VERSION 5.7 ;
  DIVIDERCHAR "/" ;
  BUSBITCHARS "[]" ;
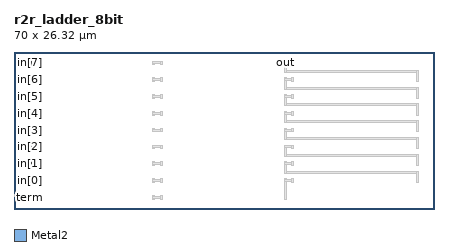
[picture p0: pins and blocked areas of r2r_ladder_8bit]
MACRO r2r_ladder_8bit
  CLASS BLOCK ;
  FOREIGN r2r_ladder_8bit 0.000 0.000 ;
  ORIGIN 0.000 0.000 ;
  SIZE 70.000 BY 26.320 ;
  SYMMETRY X Y ;
  PIN term
    DIRECTION INPUT ;
    USE SIGNAL ;
    PORT
      LAYER Metal2 ;
        RECT 2.340 1.560 2.900 2.360 ;
    END
  END term
  PIN in[0]
    DIRECTION INPUT ;
    USE SIGNAL ;
    PORT
      LAYER Metal2 ;
        RECT 2.340 4.360 2.900 5.160 ;
    END
  END in[0]
  PIN in[1]
    DIRECTION INPUT ;
    USE SIGNAL ;
    PORT
      LAYER Metal2 ;
        RECT 2.340 7.160 2.900 7.960 ;
    END
  END in[1]
  PIN in[2]
    DIRECTION INPUT ;
    USE SIGNAL ;
    PORT
      LAYER Metal2 ;
        RECT 2.340 9.960 2.900 10.760 ;
    END
  END in[2]
  PIN in[3]
    DIRECTION INPUT ;
    USE SIGNAL ;
    PORT
      LAYER Metal2 ;
        RECT 2.340 12.760 2.900 13.560 ;
    END
  END in[3]
  PIN in[4]
    DIRECTION INPUT ;
    USE SIGNAL ;
    PORT
      LAYER Metal2 ;
        RECT 2.340 15.560 2.900 16.360 ;
    END
  END in[4]
  PIN in[5]
    DIRECTION INPUT ;
    USE SIGNAL ;
    PORT
      LAYER Metal2 ;
        RECT 2.340 18.360 2.900 19.160 ;
    END
  END in[5]
  PIN in[6]
    DIRECTION INPUT ;
    USE SIGNAL ;
    PORT
      LAYER Metal2 ;
        RECT 2.340 21.160 2.900 21.960 ;
    END
  END in[6]
  PIN in[7]
    DIRECTION INPUT ;
    USE SIGNAL ;
    PORT
      LAYER Metal2 ;
        RECT 2.340 23.960 2.900 24.760 ;
    END
  END in[7]
  PIN out
    DIRECTION OUTPUT ;
    USE SIGNAL ;
    PORT
      LAYER Metal2 ;
        RECT 44.920 23.960 45.480 24.760 ;
    END
  END out
  OBS
      LAYER Metal1 ;
        RECT 2.450 2.160 2.790 2.260 ;
        RECT 2.420 1.760 2.820 2.160 ;
        RECT 2.450 1.660 2.790 1.760 ;
        RECT 23.110 1.660 23.450 1.790 ;
        RECT 23.110 2.130 23.450 2.260 ;
        RECT 23.110 1.790 24.370 2.130 ;
        RECT 24.370 1.660 24.710 2.260 ;
        RECT 2.450 4.960 2.790 5.060 ;
        RECT 2.420 4.560 2.820 4.960 ;
        RECT 2.450 4.460 2.790 4.560 ;
        RECT 23.110 4.460 23.450 4.590 ;
        RECT 23.110 4.930 23.450 5.060 ;
        RECT 23.110 4.590 24.370 4.930 ;
        RECT 24.370 4.460 24.710 5.060 ;
        RECT 45.030 1.660 45.370 4.590 ;
        RECT 45.030 4.930 45.370 5.060 ;
        RECT 45.030 4.590 46.290 4.930 ;
        RECT 46.290 4.460 46.630 5.060 ;
        RECT 2.450 7.760 2.790 7.860 ;
        RECT 2.420 7.360 2.820 7.760 ;
        RECT 2.450 7.260 2.790 7.360 ;
        RECT 23.110 7.260 23.450 7.390 ;
        RECT 23.110 7.730 23.450 7.860 ;
        RECT 23.110 7.390 24.370 7.730 ;
        RECT 24.370 7.260 24.710 7.860 ;
        RECT 45.370 5.990 67.150 6.330 ;
        RECT 45.030 5.990 45.370 7.390 ;
        RECT 67.150 4.460 67.490 6.330 ;
        RECT 45.030 7.730 45.370 7.860 ;
        RECT 45.030 7.390 46.290 7.730 ;
        RECT 46.290 7.260 46.630 7.860 ;
        RECT 2.450 10.560 2.790 10.660 ;
        RECT 2.420 10.160 2.820 10.560 ;
        RECT 2.450 10.060 2.790 10.160 ;
        RECT 23.110 10.060 23.450 10.190 ;
        RECT 23.110 10.530 23.450 10.660 ;
        RECT 23.110 10.190 24.370 10.530 ;
        RECT 24.370 10.060 24.710 10.660 ;
        RECT 45.370 8.790 67.150 9.130 ;
        RECT 45.030 8.790 45.370 10.190 ;
        RECT 67.150 7.260 67.490 9.130 ;
        RECT 45.030 10.530 45.370 10.660 ;
        RECT 45.030 10.190 46.290 10.530 ;
        RECT 46.290 10.060 46.630 10.660 ;
        RECT 2.450 13.360 2.790 13.460 ;
        RECT 2.420 12.960 2.820 13.360 ;
        RECT 2.450 12.860 2.790 12.960 ;
        RECT 23.110 12.860 23.450 12.990 ;
        RECT 23.110 13.330 23.450 13.460 ;
        RECT 23.110 12.990 24.370 13.330 ;
        RECT 24.370 12.860 24.710 13.460 ;
        RECT 45.370 11.590 67.150 11.930 ;
        RECT 45.030 11.590 45.370 12.990 ;
        RECT 67.150 10.060 67.490 11.930 ;
        RECT 45.030 13.330 45.370 13.460 ;
        RECT 45.030 12.990 46.290 13.330 ;
        RECT 46.290 12.860 46.630 13.460 ;
        RECT 2.450 16.160 2.790 16.260 ;
        RECT 2.420 15.760 2.820 16.160 ;
        RECT 2.450 15.660 2.790 15.760 ;
        RECT 23.110 15.660 23.450 15.790 ;
        RECT 23.110 16.130 23.450 16.260 ;
        RECT 23.110 15.790 24.370 16.130 ;
        RECT 24.370 15.660 24.710 16.260 ;
        RECT 45.370 14.390 67.150 14.730 ;
        RECT 45.030 14.390 45.370 15.790 ;
        RECT 67.150 12.860 67.490 14.730 ;
        RECT 45.030 16.130 45.370 16.260 ;
        RECT 45.030 15.790 46.290 16.130 ;
        RECT 46.290 15.660 46.630 16.260 ;
        RECT 2.450 18.960 2.790 19.060 ;
        RECT 2.420 18.560 2.820 18.960 ;
        RECT 2.450 18.460 2.790 18.560 ;
        RECT 23.110 18.460 23.450 18.590 ;
        RECT 23.110 18.930 23.450 19.060 ;
        RECT 23.110 18.590 24.370 18.930 ;
        RECT 24.370 18.460 24.710 19.060 ;
        RECT 45.370 17.190 67.150 17.530 ;
        RECT 45.030 17.190 45.370 18.590 ;
        RECT 67.150 15.660 67.490 17.530 ;
        RECT 45.030 18.930 45.370 19.060 ;
        RECT 45.030 18.590 46.290 18.930 ;
        RECT 46.290 18.460 46.630 19.060 ;
        RECT 2.450 21.760 2.790 21.860 ;
        RECT 2.420 21.360 2.820 21.760 ;
        RECT 2.450 21.260 2.790 21.360 ;
        RECT 23.110 21.260 23.450 21.390 ;
        RECT 23.110 21.730 23.450 21.860 ;
        RECT 23.110 21.390 24.370 21.730 ;
        RECT 24.370 21.260 24.710 21.860 ;
        RECT 45.370 19.990 67.150 20.330 ;
        RECT 45.030 19.990 45.370 21.390 ;
        RECT 67.150 18.460 67.490 20.330 ;
        RECT 45.030 21.730 45.370 21.860 ;
        RECT 45.030 21.390 46.290 21.730 ;
        RECT 46.290 21.260 46.630 21.860 ;
        RECT 2.450 24.560 2.790 24.660 ;
        RECT 2.420 24.160 2.820 24.560 ;
        RECT 2.450 24.060 2.790 24.160 ;
        RECT 23.110 24.060 23.450 24.190 ;
        RECT 23.110 24.530 23.450 24.660 ;
        RECT 23.110 24.190 24.370 24.530 ;
        RECT 24.370 24.060 24.710 24.660 ;
        RECT 45.030 24.560 45.370 24.660 ;
        RECT 45.000 24.160 45.400 24.560 ;
        RECT 45.370 22.790 67.150 23.130 ;
        RECT 45.030 22.790 45.370 24.160 ;
        RECT 67.150 21.260 67.490 23.130 ;
      LAYER Via1 ;
        RECT 2.490 1.830 2.750 2.090 ;
        RECT 2.490 4.630 2.750 4.890 ;
        RECT 2.490 7.430 2.750 7.690 ;
        RECT 2.490 10.230 2.750 10.490 ;
        RECT 2.490 13.030 2.750 13.290 ;
        RECT 2.490 15.830 2.750 16.090 ;
        RECT 2.490 18.630 2.750 18.890 ;
        RECT 2.490 21.430 2.750 21.690 ;
        RECT 2.490 24.230 2.750 24.490 ;
        RECT 45.070 24.230 45.330 24.490 ;
  END
END r2r_ladder_8bit
END LIBRARY
